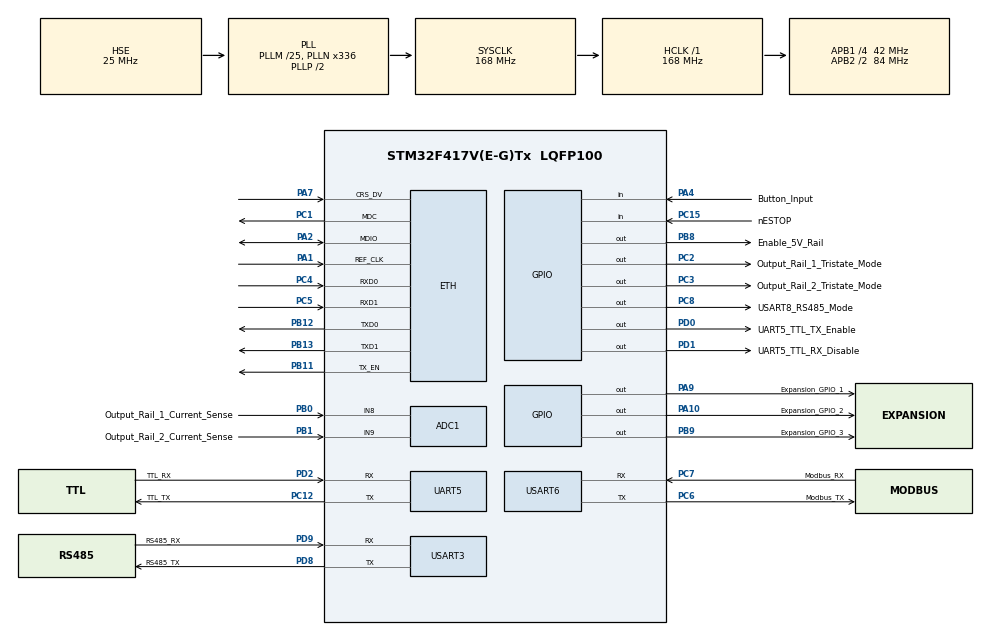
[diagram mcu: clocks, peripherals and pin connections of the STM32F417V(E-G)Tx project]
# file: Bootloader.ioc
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ADC1.Channel-0\#ChannelRegularConversion=ADC_CHANNEL_8
ADC1.NbrOfConversionFlag=1
ADC1.Rank-0\#ChannelRegularConversion=1
ADC1.SamplingTime-0\#ChannelRegularConversion=ADC_SAMPLETIME_3CYCLES
ADC1.master=1
ETH.MediaInterface=HAL_ETH_RMII_MODE
FREERTOS.Tasks01=defaultTask,24,128,StartDefaultTask,Default,NULL,Dynamic,NULL,NULL
FREERTOS.configENABLE_FPU=1
LWIP.BSP.number=1
LWIP.Version=v2.1.2_Cube
LWIP0.BSP.STBoard=false
LWIP0.BSP.api=BSP_COMPONENT_DRIVER
LWIP0.BSP.component=LAN8742
LWIP0.BSP.instance=LAN8742
LWIP0.BSP.name=Driver_PHY
LWIP0.BSP.semaphore=S_LAN8742
LWIP0.BSP.solution=LAN8742
Mcu.Family=STM32F4
Mcu.Name=STM32F417V(E-G)Tx
Mcu.Package=LQFP100
NVIC.ETH_IRQn=true\:5\:0\:false\:false\:true\:true\:false\:true\:true
NVIC.PriorityGroup=NVIC_PRIORITYGROUP_4
NVIC.TIM1_UP_TIM10_IRQn=true\:15\:0\:false\:false\:true\:false\:false\:true\:true
NVIC.TimeBase=TIM1_UP_TIM10_IRQn
NVIC.TimeBaseIP=TIM1
PA1.Mode=RMII
PA1.Signal=ETH_REF_CLK
PA10.GPIO_Label=Expansion_GPIO_2
PA10.Signal=GPIO_Output
PA13.Mode=Trace_Asynchronous_SW
PA13.Signal=SYS_JTMS-SWDIO
PA14.Mode=Trace_Asynchronous_SW
PA14.Signal=SYS_JTCK-SWCLK
PA2.Mode=RMII
PA2.Signal=ETH_MDIO
PA4.GPIO_Label=Button_Input
PA4.Signal=GPIO_Input
PA7.Mode=RMII
PA7.Signal=ETH_CRS_DV
PA9.GPIO_Label=Expansion_GPIO_1
PA9.Signal=GPIO_Output
PB0.GPIO_Label=Output_Rail_1_Current_Sense
PB0.Signal=SharedAnalog_PB0
PB1.GPIO_Label=Output_Rail_2_Current_Sense
PB1.Signal=SharedAnalog_PB1
PB11.Mode=RMII
PB11.Signal=ETH_TX_EN
PB12.Mode=RMII
PB12.Signal=ETH_TXD0
PB13.Mode=RMII
PB13.Signal=ETH_TXD1
PB3.Mode=Trace_Asynchronous_SW
PB3.Signal=SYS_JTDO-SWO
PB8.GPIO_Label=Enable_5V_Rail
PB8.Signal=GPIO_Output
PB9.GPIO_Label=Expansion_GPIO_3
PB9.Signal=GPIO_Output
PC1.Mode=RMII
PC1.Signal=ETH_MDC
PC12.GPIO_Label=TTL_TX
PC12.Mode=Asynchronous
PC12.Signal=UART5_TX
PC15-OSC32_OUT.GPIO_Label=nESTOP
PC15-OSC32_OUT.Signal=GPIO_Input
PC2.GPIO_Label=Output_Rail_1_Tristate_Mode
PC2.Signal=GPIO_Output
PC3.GPIO_Label=Output_Rail_2_Tristate_Mode
PC3.Signal=GPIO_Output
PC4.Mode=RMII
PC4.Signal=ETH_RXD0
PC5.Mode=RMII
PC5.Signal=ETH_RXD1
PC6.GPIO_Label=Modbus_TX
PC6.Mode=Asynchronous
PC6.Signal=USART6_TX
PC7.GPIO_Label=Modbus_RX
PC7.Mode=Asynchronous
PC7.Signal=USART6_RX
PC8.GPIO_Label=USART8_RS485_Mode
PC8.Signal=GPIO_Output
PD0.GPIO_Label=UART5_TTL_TX_Enable
PD0.Signal=GPIO_Output
PD1.GPIO_Label=UART5_TTL_RX_Disable
PD1.Signal=GPIO_Output
PD2.GPIO_Label=TTL_RX
PD2.Mode=Asynchronous
PD2.Signal=UART5_RX
PD8.GPIO_Label=RS485_TX
PD8.Mode=Asynchronous
PD8.Signal=USART3_TX
PD9.GPIO_Label=RS485_RX
PD9.Mode=Asynchronous
PD9.Signal=USART3_RX
PH0-OSC_IN.Mode=HSE-External-Oscillator
PH0-OSC_IN.Signal=RCC_OSC_IN
PH1-OSC_OUT.Mode=HSE-External-Oscillator
PH1-OSC_OUT.Signal=RCC_OSC_OUT
ProjectManager.HeapSize=0x200
ProjectManager.StackSize=0x400
ProjectManager.TargetToolchain=STM32CubeIDE
RCC.48MHZClocksFreq_Value=84000000
RCC.AHBFreq_Value=168000000
RCC.APB1CLKDivider=RCC_HCLK_DIV4
RCC.APB1Freq_Value=42000000
RCC.APB1TimFreq_Value=84000000
RCC.APB2CLKDivider=RCC_HCLK_DIV2
RCC.APB2Freq_Value=84000000
RCC.APB2TimFreq_Value=168000000
RCC.CortexFreq_Value=168000000
RCC.HCLKFreq_Value=168000000
RCC.HSE_VALUE=25000000
RCC.HSI_VALUE=16000000
RCC.LSE_VALUE=32768
RCC.PLLM=25
RCC.PLLN=336
RCC.PLLSourceVirtual=RCC_PLLSOURCE_HSE
RCC.RCC_RTC_Clock_Source_FROM_HSE=RCC_RTCCLKSOURCE_HSE_DIV30
RCC.SYSCLKFreq_VALUE=168000000
RCC.SYSCLKSource=RCC_SYSCLKSOURCE_PLLCLK
RCC.VCOOutputFreq_Value=336000000
SH.SharedAnalog_PB0.0=GPIO_Analog
SH.SharedAnalog_PB0.1=ADC1_IN8,IN8
SH.SharedAnalog_PB1.0=GPIO_Analog
SH.SharedAnalog_PB1.1=ADC1_IN9,IN9
UART5.VirtualMode=Asynchronous
USART3.VirtualMode=VM_ASYNC
USART6.VirtualMode=VM_ASYNC
VP_CRC_VS_CRC.Mode=CRC_Activate
VP_FREERTOS_VS_CMSIS_V2.Mode=CMSIS_V2
VP_HASH_VS_HASH.Mode=HASH_Activate
VP_LWIP_VS_Enabled.Mode=Enabled
VP_RTC_VS_RTC_Activate.Mode=RTC_Enabled
VP_SYS_VS_tim1.Mode=TIM1
board=custom

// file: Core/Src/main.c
/* USER CODE BEGIN Header */
/**
  ******************************************************************************
  * @file           : main.c
  * @brief          : Main program body
  ******************************************************************************
  * @attention
  *
  * Copyright (c) 2026 STMicroelectronics.
  * All rights reserved.
  *
  * This software is licensed under terms that can be found in the LICENSE file
  * in the root directory of this software component.
  * If no LICENSE file comes with this software, it is provided AS-IS.
  *
  ******************************************************************************
  */
/* USER CODE END Header */
#include "main.h"
#include "cmsis_os.h"
#include "lwip.h"

/* USER CODE BEGIN Includes */
#include "FreeRTOS.h"
#include "resident_main.h"
#include "task.h"
#include <stdio.h>
/* USER CODE END Includes */

ADC_HandleTypeDef hadc1;

CRC_HandleTypeDef hcrc;

HASH_HandleTypeDef hhash;

RTC_HandleTypeDef hrtc;

UART_HandleTypeDef huart5;
UART_HandleTypeDef huart3;
UART_HandleTypeDef huart6;

/* Definitions for defaultTask */
osThreadId_t defaultTaskHandle;
StaticTask_t defaultTaskControlBlock;
StackType_t defaultTaskStack[768];
const osThreadAttr_t defaultTask_attributes = {
  .name = "Resident",
  .cb_mem = &defaultTaskControlBlock,
  .cb_size = sizeof(defaultTaskControlBlock),
  .stack_mem = defaultTaskStack,
  .stack_size = sizeof(defaultTaskStack),
  .priority = (osPriority_t) osPriorityNormal,
};

void SystemClock_Config(void);
static void MX_GPIO_Init(void);
static void MX_ADC1_Init(void);
static void MX_CRC_Init(void);
static void MX_HASH_Init(void);
static void MX_RTC_Init(void);
static void MX_UART5_Init(void);
static void MX_USART3_UART_Init(void);
static void MX_USART6_UART_Init(void);
void StartDefaultTask(void *argument);

/* USER CODE BEGIN 0 */
static void SWO_Init(void)
{
  /* Enable trace and route ITM/SWO out through the debugger. */
  CoreDebug->DEMCR |= CoreDebug_DEMCR_TRCENA_Msk;

  /* Unlock ITM on parts that implement the lock register. */
  ITM->LAR = 0xC5ACCE55UL;

  /* Select async SWO; the debugger launch config handles the capture rate. */
  TPI->SPPR = 2U;

  ITM->TCR = ITM_TCR_ITMENA_Msk | ITM_TCR_SWOENA_Msk;
  ITM->TER = 1U;
}

int _write(int file, char *ptr, int len)
{
  (void)file;

  for (int i = 0; i < len; i++)
  {
    ITM_SendChar((uint32_t)(*ptr++));
  }

  return len;
}

/* USER CODE END 0 */

int main(void)
{

  /* MCU Configuration--------------------------------------------------------*/

  /* Reset of all peripherals, Initializes the Flash interface and the Systick. */
  HAL_Init();

  /* USER CODE BEGIN Init */
  setvbuf(stdout, NULL, _IONBF, 0);
  /* USER CODE END Init */

  /* Configure the system clock */
  SystemClock_Config();

  SWO_Init();

  /* USER CODE BEGIN SysInit */
  printf("SWV: printf retarget online\r\n");

  /* USER CODE END SysInit */

  /* Initialize all configured peripherals */
  MX_GPIO_Init();
  HAL_GPIO_WritePin(Engineer_LED_Green_GPIO_Port, Engineer_LED_Green_Pin, GPIO_PIN_RESET);
  HAL_GPIO_WritePin(Engineer_LED_Red_GPIO_Port, Engineer_LED_Red_Pin, GPIO_PIN_SET);
  MX_ADC1_Init();
  MX_CRC_Init();
  MX_HASH_Init();
  MX_RTC_Init();
  MX_UART5_Init();
  MX_USART3_UART_Init();
  MX_USART6_UART_Init();

  /* Init scheduler */
  osKernelInitialize();

  /* Create the thread(s) */
  /* creation of defaultTask */
  defaultTaskHandle = osThreadNew(StartDefaultTask, NULL, &defaultTask_attributes);

  /* Start scheduler */
  osKernelStart();

  /* We should never get here as control is now taken by the scheduler */

  /* Infinite loop */
  while (1)
  {

  }
}

void SystemClock_Config(void)
{
  RCC_OscInitTypeDef RCC_OscInitStruct = {0};
  RCC_ClkInitTypeDef RCC_ClkInitStruct = {0};

  /** Configure the main internal regulator output voltage
  */
  __HAL_RCC_PWR_CLK_ENABLE();
  __HAL_PWR_VOLTAGESCALING_CONFIG(PWR_REGULATOR_VOLTAGE_SCALE1);

  /** Initializes the RCC Oscillators according to the specified parameters
  * in the RCC_OscInitTypeDef structure.
  */
  RCC_OscInitStruct.OscillatorType = RCC_OSCILLATORTYPE_LSI|RCC_OSCILLATORTYPE_HSE;
  RCC_OscInitStruct.HSEState = RCC_HSE_ON;
  RCC_OscInitStruct.LSIState = RCC_LSI_ON;
  RCC_OscInitStruct.PLL.PLLState = RCC_PLL_ON;
  RCC_OscInitStruct.PLL.PLLSource = RCC_PLLSOURCE_HSE;
  RCC_OscInitStruct.PLL.PLLM = 25;
  RCC_OscInitStruct.PLL.PLLN = 336;
  RCC_OscInitStruct.PLL.PLLP = RCC_PLLP_DIV2;
  RCC_OscInitStruct.PLL.PLLQ = 4;
  if (HAL_RCC_OscConfig(&RCC_OscInitStruct) != HAL_OK)
  {
    Error_Handler();
  }

  /** Initializes the CPU, AHB and APB buses clocks
  */
  RCC_ClkInitStruct.ClockType = RCC_CLOCKTYPE_HCLK|RCC_CLOCKTYPE_SYSCLK
                              |RCC_CLOCKTYPE_PCLK1|RCC_CLOCKTYPE_PCLK2;
  RCC_ClkInitStruct.SYSCLKSource = RCC_SYSCLKSOURCE_PLLCLK;
  RCC_ClkInitStruct.AHBCLKDivider = RCC_SYSCLK_DIV1;
  RCC_ClkInitStruct.APB1CLKDivider = RCC_HCLK_DIV4;
  RCC_ClkInitStruct.APB2CLKDivider = RCC_HCLK_DIV2;

  if (HAL_RCC_ClockConfig(&RCC_ClkInitStruct, FLASH_LATENCY_5) != HAL_OK)
  {
    Error_Handler();
  }
}

static void MX_ADC1_Init(void)
{

  ADC_ChannelConfTypeDef sConfig = {0};

  /** Configure the global features of the ADC (Clock, Resolution, Data Alignment and number of conversion)
  */
  hadc1.Instance = ADC1;
  hadc1.Init.ClockPrescaler = ADC_CLOCK_SYNC_PCLK_DIV4;
  hadc1.Init.Resolution = ADC_RESOLUTION_12B;
  hadc1.Init.ScanConvMode = DISABLE;
  hadc1.Init.ContinuousConvMode = DISABLE;
  hadc1.Init.DiscontinuousConvMode = DISABLE;
  hadc1.Init.ExternalTrigConvEdge = ADC_EXTERNALTRIGCONVEDGE_NONE;
  hadc1.Init.ExternalTrigConv = ADC_SOFTWARE_START;
  hadc1.Init.DataAlign = ADC_DATAALIGN_RIGHT;
  hadc1.Init.NbrOfConversion = 1;
  hadc1.Init.DMAContinuousRequests = DISABLE;
  hadc1.Init.EOCSelection = ADC_EOC_SINGLE_CONV;
  if (HAL_ADC_Init(&hadc1) != HAL_OK)
  {
    Error_Handler();
  }

  /** Configure for the selected ADC regular channel its corresponding rank in the sequencer and its sample time.
  */
  sConfig.Channel = ADC_CHANNEL_8;
  sConfig.Rank = 1;
  sConfig.SamplingTime = ADC_SAMPLETIME_3CYCLES;
  if (HAL_ADC_ConfigChannel(&hadc1, &sConfig) != HAL_OK)
  {
    Error_Handler();
  }

}

static void MX_CRC_Init(void)
{

  hcrc.Instance = CRC;
  if (HAL_CRC_Init(&hcrc) != HAL_OK)
  {
    Error_Handler();
  }

}

static void MX_HASH_Init(void)
{

  hhash.Init.DataType = HASH_DATATYPE_32B;
  if (HAL_HASH_Init(&hhash) != HAL_OK)
  {
    Error_Handler();
  }

}

static void MX_RTC_Init(void)
{

  /** Initialize RTC Only
  */
  hrtc.Instance = RTC;
  hrtc.Init.HourFormat = RTC_HOURFORMAT_24;
  hrtc.Init.AsynchPrediv = 127;
  hrtc.Init.SynchPrediv = 255;
  hrtc.Init.OutPut = RTC_OUTPUT_DISABLE;
  hrtc.Init.OutPutPolarity = RTC_OUTPUT_POLARITY_HIGH;
  hrtc.Init.OutPutType = RTC_OUTPUT_TYPE_OPENDRAIN;
  if (HAL_RTC_Init(&hrtc) != HAL_OK)
  {
    Error_Handler();
  }

}

static void MX_UART5_Init(void)
{

  huart5.Instance = UART5;
  huart5.Init.BaudRate = 115200;
  huart5.Init.WordLength = UART_WORDLENGTH_8B;
  huart5.Init.StopBits = UART_STOPBITS_1;
  huart5.Init.Parity = UART_PARITY_NONE;
  huart5.Init.Mode = UART_MODE_TX_RX;
  huart5.Init.HwFlowCtl = UART_HWCONTROL_NONE;
  huart5.Init.OverSampling = UART_OVERSAMPLING_16;
  if (HAL_UART_Init(&huart5) != HAL_OK)
  {
    Error_Handler();
  }

}

static void MX_USART3_UART_Init(void)
{

  huart3.Instance = USART3;
  huart3.Init.BaudRate = 115200;
  huart3.Init.WordLength = UART_WORDLENGTH_8B;
  huart3.Init.StopBits = UART_STOPBITS_1;
  huart3.Init.Parity = UART_PARITY_NONE;
  huart3.Init.Mode = UART_MODE_TX_RX;
  huart3.Init.HwFlowCtl = UART_HWCONTROL_NONE;
  huart3.Init.OverSampling = UART_OVERSAMPLING_16;
  if (HAL_UART_Init(&huart3) != HAL_OK)
  {
    Error_Handler();
  }

}

static void MX_USART6_UART_Init(void)
{

  huart6.Instance = USART6;
  huart6.Init.BaudRate = 115200;
  huart6.Init.WordLength = UART_WORDLENGTH_8B;
  huart6.Init.StopBits = UART_STOPBITS_1;
  huart6.Init.Parity = UART_PARITY_NONE;
  huart6.Init.Mode = UART_MODE_TX_RX;
  huart6.Init.HwFlowCtl = UART_HWCONTROL_NONE;
  huart6.Init.OverSampling = UART_OVERSAMPLING_16;
  if (HAL_UART_Init(&huart6) != HAL_OK)
  {
    Error_Handler();
  }

}

static void MX_GPIO_Init(void)
{
  GPIO_InitTypeDef GPIO_InitStruct = {0};

  /* GPIO Ports Clock Enable */
  __HAL_RCC_GPIOC_CLK_ENABLE();
  __HAL_RCC_GPIOH_CLK_ENABLE();
  __HAL_RCC_GPIOA_CLK_ENABLE();
  __HAL_RCC_GPIOB_CLK_ENABLE();
  __HAL_RCC_GPIOD_CLK_ENABLE();

  /*Configure GPIO pin Output Level */
  HAL_GPIO_WritePin(GPIOC, User_LED_Red_Pin|Output_Rail_1_Tristate_Mode_Pin|Output_Rail_2_Tristate_Mode_Pin|USART8_RS485_Mode_Pin, GPIO_PIN_RESET);

  /*Configure GPIO pin Output Level */
  HAL_GPIO_WritePin(GPIOA, User_Led_Gre_Pin|Expansion_GPIO_1_Pin|Expansion_GPIO_2_Pin, GPIO_PIN_RESET);

  /*Configure GPIO pin Output Level */
  HAL_GPIO_WritePin(GPIOD, UART5_TTL_TX_Enable_Pin|UART5_TTL_RX_Disable_Pin|Engineer_LED_Red_Pin|Engineer_LED_Green_Pin, GPIO_PIN_RESET);

  /*Configure GPIO pin Output Level */
  HAL_GPIO_WritePin(GPIOB, Enable_5V_Rail_Pin|Expansion_GPIO_3_Pin, GPIO_PIN_RESET);

  /*Configure GPIO pin : nESTOP_Pin */
  GPIO_InitStruct.Pin = nESTOP_Pin;
  GPIO_InitStruct.Mode = GPIO_MODE_INPUT;
  GPIO_InitStruct.Pull = GPIO_NOPULL;
  HAL_GPIO_Init(nESTOP_GPIO_Port, &GPIO_InitStruct);

  /*Configure GPIO pins : User_LED_Red_Pin Output_Rail_1_Tristate_Mode_Pin Output_Rail_2_Tristate_Mode_Pin USART8_RS485_Mode_Pin */
  GPIO_InitStruct.Pin = User_LED_Red_Pin|Output_Rail_1_Tristate_Mode_Pin|Output_Rail_2_Tristate_Mode_Pin|USART8_RS485_Mode_Pin;
  GPIO_InitStruct.Mode = GPIO_MODE_OUTPUT_PP;
  GPIO_InitStruct.Pull = GPIO_NOPULL;
  GPIO_InitStruct.Speed = GPIO_SPEED_FREQ_LOW;
  HAL_GPIO_Init(GPIOC, &GPIO_InitStruct);

  /*Configure GPIO pins : User_Led_Gre_Pin Expansion_GPIO_1_Pin Expansion_GPIO_2_Pin */
  GPIO_InitStruct.Pin = User_Led_Gre_Pin|Expansion_GPIO_1_Pin|Expansion_GPIO_2_Pin;
  GPIO_InitStruct.Mode = GPIO_MODE_OUTPUT_PP;
  GPIO_InitStruct.Pull = GPIO_NOPULL;
  GPIO_InitStruct.Speed = GPIO_SPEED_FREQ_LOW;
  HAL_GPIO_Init(GPIOA, &GPIO_InitStruct);

  /*Configure GPIO pin : Button_Input_Pin */
  GPIO_InitStruct.Pin = Button_Input_Pin;
  GPIO_InitStruct.Mode = GPIO_MODE_INPUT;
  GPIO_InitStruct.Pull = GPIO_NOPULL;
  HAL_GPIO_Init(Button_Input_GPIO_Port, &GPIO_InitStruct);

  /*Configure GPIO pins : UART5_TTL_TX_Enable_Pin UART5_TTL_RX_Disable_Pin Engineer_LED_Red_Pin Engineer_LED_Green_Pin */
  GPIO_InitStruct.Pin = UART5_TTL_TX_Enable_Pin|UART5_TTL_RX_Disable_Pin|Engineer_LED_Red_Pin|Engineer_LED_Green_Pin;
  GPIO_InitStruct.Mode = GPIO_MODE_OUTPUT_PP;
  GPIO_InitStruct.Pull = GPIO_NOPULL;
  GPIO_InitStruct.Speed = GPIO_SPEED_FREQ_LOW;
  HAL_GPIO_Init(GPIOD, &GPIO_InitStruct);

  /*Configure GPIO pins : Enable_5V_Rail_Pin Expansion_GPIO_3_Pin */
  GPIO_InitStruct.Pin = Enable_5V_Rail_Pin|Expansion_GPIO_3_Pin;
  GPIO_InitStruct.Mode = GPIO_MODE_OUTPUT_PP;
  GPIO_InitStruct.Pull = GPIO_NOPULL;
  GPIO_InitStruct.Speed = GPIO_SPEED_FREQ_LOW;
  HAL_GPIO_Init(GPIOB, &GPIO_InitStruct);

}

void StartDefaultTask(void *argument)
{
  /* USER CODE BEGIN 5 */
  resident_main_task(argument);
  /* USER CODE END 5 */
}

void HAL_TIM_PeriodElapsedCallback(TIM_HandleTypeDef *htim)
{
  if (htim->Instance == TIM1) {
    HAL_IncTick();
  }
}

void Error_Handler(void)
{
  __disable_irq();
  while (1)
  {
  }
}

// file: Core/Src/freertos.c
/* USER CODE BEGIN Header */
/**
  ******************************************************************************
  * File Name          : freertos.c
  * Description        : Code for freertos applications
  ******************************************************************************
  * @attention
  *
  * Copyright (c) 2026 STMicroelectronics.
  * All rights reserved.
  *
  * This software is licensed under terms that can be found in the LICENSE file
  * in the root directory of this software component.
  * If no LICENSE file comes with this software, it is provided AS-IS.
  *
  ******************************************************************************
  */
/* USER CODE END Header */

#include "FreeRTOS.h"
#include "task.h"
#include "main.h"
#include <stdio.h>

/* USER CODE BEGIN Application */

/* Call from GDB when halted: call debug_freertos_print_stack_watermarks()
 * (ITM/SWO or semihosting printf must work for output.) */
void debug_freertos_print_stack_watermarks(void)
{
  static TaskStatus_t rows[24];
  const UBaseType_t cap = (UBaseType_t)(sizeof(rows) / sizeof(rows[0]));
  const UBaseType_t n = uxTaskGetSystemState(rows, cap, NULL);

  (void)printf("Task stack high water (FreeRTOS \"words\", typically 4 bytes each)\r\n");
  for (UBaseType_t i = 0U; i < n; i++)
  {
    (void)printf("  %-16s  min_free_words=%u\r\n", rows[i].pcTaskName,
                   (unsigned int)rows[i].usStackHighWaterMark);
  }
}

/* USER CODE END Application */
